VERSION 5.7 ;
  NOWIREEXTENSIONATPIN ON ;
  DIVIDERCHAR "/" ;
  BUSBITCHARS "[]" ;
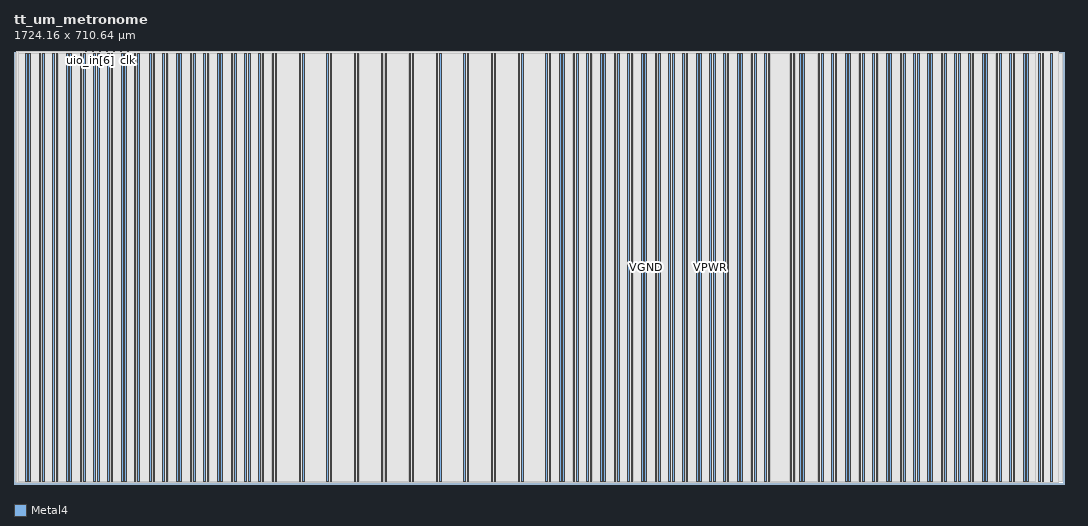
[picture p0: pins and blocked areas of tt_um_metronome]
MACRO tt_um_metronome
  CLASS BLOCK ;
  FOREIGN tt_um_metronome ;
  ORIGIN 0.000 0.000 ;
  SIZE 1724.160 BY 710.640 ;
  PIN VGND
    DIRECTION INOUT ;
    USE GROUND ;
    PORT
      LAYER Metal4 ;
        RECT 24.480 3.780 27.290 706.860 ;
    END
    PORT
      LAYER Metal4 ;
        RECT 46.960 3.780 49.770 706.860 ;
    END
    PORT
      LAYER Metal4 ;
        RECT 69.440 3.780 72.250 706.860 ;
    END
    PORT
      LAYER Metal4 ;
        RECT 91.920 3.780 94.730 706.860 ;
    END
    PORT
      LAYER Metal4 ;
        RECT 114.400 3.780 117.210 706.860 ;
    END
    PORT
      LAYER Metal4 ;
        RECT 136.880 3.780 139.690 706.860 ;
    END
    PORT
      LAYER Metal4 ;
        RECT 159.360 3.780 162.170 706.860 ;
    END
    PORT
      LAYER Metal4 ;
        RECT 181.840 3.780 184.650 706.860 ;
    END
    PORT
      LAYER Metal4 ;
        RECT 202.550 3.780 205.360 706.860 ;
    END
    PORT
      LAYER Metal4 ;
        RECT 228.300 3.780 231.110 706.860 ;
    END
    PORT
      LAYER Metal4 ;
        RECT 249.950 3.780 252.760 706.860 ;
    END
    PORT
      LAYER Metal4 ;
        RECT 272.430 3.780 275.240 706.860 ;
    END
    PORT
      LAYER Metal4 ;
        RECT 294.910 3.780 297.720 706.860 ;
    END
    PORT
      LAYER Metal4 ;
        RECT 317.390 3.780 320.200 706.860 ;
    END
    PORT
      LAYER Metal4 ;
        RECT 339.870 3.780 342.680 706.860 ;
    END
    PORT
      LAYER Metal4 ;
        RECT 362.350 3.780 365.160 706.860 ;
    END
    PORT
      LAYER Metal4 ;
        RECT 384.830 3.780 387.640 706.860 ;
    END
    PORT
      LAYER Metal4 ;
        RECT 407.310 3.780 410.120 706.860 ;
    END
    PORT
      LAYER Metal4 ;
        RECT 429.480 3.560 431.580 707.080 ;
    END
    PORT
      LAYER Metal4 ;
        RECT 474.440 3.560 476.540 707.080 ;
    END
    PORT
      LAYER Metal4 ;
        RECT 519.400 3.560 521.500 707.080 ;
    END
    PORT
      LAYER Metal4 ;
        RECT 564.360 3.560 566.460 707.080 ;
    END
    PORT
      LAYER Metal4 ;
        RECT 609.320 3.560 611.420 707.080 ;
    END
    PORT
      LAYER Metal4 ;
        RECT 654.280 3.560 656.380 707.080 ;
    END
    PORT
      LAYER Metal4 ;
        RECT 699.240 3.560 701.340 707.080 ;
    END
    PORT
      LAYER Metal4 ;
        RECT 744.200 3.560 746.300 707.080 ;
    END
    PORT
      LAYER Metal4 ;
        RECT 789.160 3.560 791.260 707.080 ;
    END
    PORT
      LAYER Metal4 ;
        RECT 834.120 3.560 836.220 707.080 ;
    END
    PORT
      LAYER Metal4 ;
        RECT 879.080 3.560 881.180 707.080 ;
    END
    PORT
      LAYER Metal4 ;
        RECT 901.200 3.780 904.010 706.860 ;
    END
    PORT
      LAYER Metal4 ;
        RECT 923.680 3.780 926.490 706.860 ;
    END
    PORT
      LAYER Metal4 ;
        RECT 946.160 3.780 948.970 706.860 ;
    END
    PORT
      LAYER Metal4 ;
        RECT 968.640 3.780 971.450 706.860 ;
    END
    PORT
      LAYER Metal4 ;
        RECT 991.120 3.780 993.930 706.860 ;
    END
    PORT
      LAYER Metal4 ;
        RECT 1013.600 3.780 1016.410 706.860 ;
    END
    PORT
      LAYER Metal4 ;
        RECT 1036.080 3.780 1038.890 706.860 ;
    END
    PORT
      LAYER Metal4 ;
        RECT 1058.560 3.780 1061.370 706.860 ;
    END
    PORT
      LAYER Metal4 ;
        RECT 1081.040 3.780 1083.850 706.860 ;
    END
    PORT
      LAYER Metal4 ;
        RECT 1103.520 3.780 1106.330 706.860 ;
    END
    PORT
      LAYER Metal4 ;
        RECT 1126.000 3.780 1128.810 706.860 ;
    END
    PORT
      LAYER Metal4 ;
        RECT 1148.480 3.780 1151.290 706.860 ;
    END
    PORT
      LAYER Metal4 ;
        RECT 1170.960 3.780 1173.770 706.860 ;
    END
    PORT
      LAYER Metal4 ;
        RECT 1193.440 3.780 1196.250 706.860 ;
    END
    PORT
      LAYER Metal4 ;
        RECT 1215.920 3.780 1218.730 706.860 ;
    END
    PORT
      LAYER Metal4 ;
        RECT 1238.400 3.780 1241.210 706.860 ;
    END
    PORT
      LAYER Metal4 ;
        RECT 1274.430 3.780 1277.240 706.860 ;
    END
    PORT
      LAYER Metal4 ;
        RECT 1289.880 3.780 1292.690 706.860 ;
    END
    PORT
      LAYER Metal4 ;
        RECT 1325.910 3.780 1328.720 706.860 ;
    END
    PORT
      LAYER Metal4 ;
        RECT 1348.390 3.780 1351.200 706.860 ;
    END
    PORT
      LAYER Metal4 ;
        RECT 1370.870 3.780 1373.680 706.860 ;
    END
    PORT
      LAYER Metal4 ;
        RECT 1393.350 3.780 1396.160 706.860 ;
    END
    PORT
      LAYER Metal4 ;
        RECT 1415.830 3.780 1418.640 706.860 ;
    END
    PORT
      LAYER Metal4 ;
        RECT 1438.310 3.780 1441.120 706.860 ;
    END
    PORT
      LAYER Metal4 ;
        RECT 1460.790 3.780 1463.600 706.860 ;
    END
    PORT
      LAYER Metal4 ;
        RECT 1483.270 3.780 1486.080 706.860 ;
    END
    PORT
      LAYER Metal4 ;
        RECT 1505.750 3.780 1508.560 706.860 ;
    END
    PORT
      LAYER Metal4 ;
        RECT 1528.230 3.780 1531.040 706.860 ;
    END
    PORT
      LAYER Metal4 ;
        RECT 1550.710 3.780 1553.520 706.860 ;
    END
    PORT
      LAYER Metal4 ;
        RECT 1573.190 3.780 1576.000 706.860 ;
    END
    PORT
      LAYER Metal4 ;
        RECT 1595.670 3.780 1598.480 706.860 ;
    END
    PORT
      LAYER Metal4 ;
        RECT 1618.150 3.780 1620.960 706.860 ;
    END
    PORT
      LAYER Metal4 ;
        RECT 1640.630 3.780 1643.440 706.860 ;
    END
    PORT
      LAYER Metal4 ;
        RECT 1663.110 3.780 1665.920 706.860 ;
    END
    PORT
      LAYER Metal4 ;
        RECT 1688.360 3.560 1690.460 707.080 ;
    END
  END VGND
  PIN VPWR
    DIRECTION INOUT ;
    USE POWER ;
    PORT
      LAYER Metal4 ;
        RECT 18.860 3.780 21.670 706.860 ;
    END
    PORT
      LAYER Metal4 ;
        RECT 41.340 3.780 44.150 706.860 ;
    END
    PORT
      LAYER Metal4 ;
        RECT 63.820 3.780 66.630 706.860 ;
    END
    PORT
      LAYER Metal4 ;
        RECT 86.300 3.780 89.110 706.860 ;
    END
    PORT
      LAYER Metal4 ;
        RECT 108.780 3.780 111.590 706.860 ;
    END
    PORT
      LAYER Metal4 ;
        RECT 131.260 3.780 134.070 706.860 ;
    END
    PORT
      LAYER Metal4 ;
        RECT 153.740 3.780 156.550 706.860 ;
    END
    PORT
      LAYER Metal4 ;
        RECT 176.220 3.780 179.030 706.860 ;
    END
    PORT
      LAYER Metal4 ;
        RECT 197.400 3.780 200.210 706.860 ;
    END
    PORT
      LAYER Metal4 ;
        RECT 223.150 3.780 225.960 706.860 ;
    END
    PORT
      LAYER Metal4 ;
        RECT 244.330 3.780 247.140 706.860 ;
    END
    PORT
      LAYER Metal4 ;
        RECT 266.810 3.780 269.620 706.860 ;
    END
    PORT
      LAYER Metal4 ;
        RECT 289.290 3.780 292.100 706.860 ;
    END
    PORT
      LAYER Metal4 ;
        RECT 311.770 3.780 314.580 706.860 ;
    END
    PORT
      LAYER Metal4 ;
        RECT 334.250 3.780 337.060 706.860 ;
    END
    PORT
      LAYER Metal4 ;
        RECT 356.730 3.780 359.540 706.860 ;
    END
    PORT
      LAYER Metal4 ;
        RECT 379.210 3.780 382.020 706.860 ;
    END
    PORT
      LAYER Metal4 ;
        RECT 401.690 3.780 404.500 706.860 ;
    END
    PORT
      LAYER Metal4 ;
        RECT 423.860 3.560 425.960 707.080 ;
    END
    PORT
      LAYER Metal4 ;
        RECT 468.820 3.560 470.920 707.080 ;
    END
    PORT
      LAYER Metal4 ;
        RECT 513.780 3.560 515.880 707.080 ;
    END
    PORT
      LAYER Metal4 ;
        RECT 558.740 3.560 560.840 707.080 ;
    END
    PORT
      LAYER Metal4 ;
        RECT 603.700 3.560 605.800 707.080 ;
    END
    PORT
      LAYER Metal4 ;
        RECT 648.660 3.560 650.760 707.080 ;
    END
    PORT
      LAYER Metal4 ;
        RECT 693.620 3.560 695.720 707.080 ;
    END
    PORT
      LAYER Metal4 ;
        RECT 738.580 3.560 740.680 707.080 ;
    END
    PORT
      LAYER Metal4 ;
        RECT 783.540 3.560 785.640 707.080 ;
    END
    PORT
      LAYER Metal4 ;
        RECT 828.500 3.560 830.600 707.080 ;
    END
    PORT
      LAYER Metal4 ;
        RECT 873.460 3.560 875.560 707.080 ;
    END
    PORT
      LAYER Metal4 ;
        RECT 895.580 3.780 898.390 706.860 ;
    END
    PORT
      LAYER Metal4 ;
        RECT 918.060 3.780 920.870 706.860 ;
    END
    PORT
      LAYER Metal4 ;
        RECT 940.540 3.780 943.350 706.860 ;
    END
    PORT
      LAYER Metal4 ;
        RECT 963.020 3.780 965.830 706.860 ;
    END
    PORT
      LAYER Metal4 ;
        RECT 985.500 3.780 988.310 706.860 ;
    END
    PORT
      LAYER Metal4 ;
        RECT 1007.980 3.780 1010.790 706.860 ;
    END
    PORT
      LAYER Metal4 ;
        RECT 1030.460 3.780 1033.270 706.860 ;
    END
    PORT
      LAYER Metal4 ;
        RECT 1052.940 3.780 1055.750 706.860 ;
    END
    PORT
      LAYER Metal4 ;
        RECT 1075.420 3.780 1078.230 706.860 ;
    END
    PORT
      LAYER Metal4 ;
        RECT 1097.900 3.780 1100.710 706.860 ;
    END
    PORT
      LAYER Metal4 ;
        RECT 1120.380 3.780 1123.190 706.860 ;
    END
    PORT
      LAYER Metal4 ;
        RECT 1142.860 3.780 1145.670 706.860 ;
    END
    PORT
      LAYER Metal4 ;
        RECT 1165.340 3.780 1168.150 706.860 ;
    END
    PORT
      LAYER Metal4 ;
        RECT 1187.820 3.780 1190.630 706.860 ;
    END
    PORT
      LAYER Metal4 ;
        RECT 1210.300 3.780 1213.110 706.860 ;
    END
    PORT
      LAYER Metal4 ;
        RECT 1232.780 3.780 1235.590 706.860 ;
    END
    PORT
      LAYER Metal4 ;
        RECT 1279.580 3.780 1282.390 706.860 ;
    END
    PORT
      LAYER Metal4 ;
        RECT 1295.030 3.780 1297.840 706.860 ;
    END
    PORT
      LAYER Metal4 ;
        RECT 1320.290 3.780 1323.100 706.860 ;
    END
    PORT
      LAYER Metal4 ;
        RECT 1342.770 3.780 1345.580 706.860 ;
    END
    PORT
      LAYER Metal4 ;
        RECT 1365.250 3.780 1368.060 706.860 ;
    END
    PORT
      LAYER Metal4 ;
        RECT 1387.730 3.780 1390.540 706.860 ;
    END
    PORT
      LAYER Metal4 ;
        RECT 1410.210 3.780 1413.020 706.860 ;
    END
    PORT
      LAYER Metal4 ;
        RECT 1432.690 3.780 1435.500 706.860 ;
    END
    PORT
      LAYER Metal4 ;
        RECT 1455.170 3.780 1457.980 706.860 ;
    END
    PORT
      LAYER Metal4 ;
        RECT 1477.650 3.780 1480.460 706.860 ;
    END
    PORT
      LAYER Metal4 ;
        RECT 1500.130 3.780 1502.940 706.860 ;
    END
    PORT
      LAYER Metal4 ;
        RECT 1522.610 3.780 1525.420 706.860 ;
    END
    PORT
      LAYER Metal4 ;
        RECT 1545.090 3.780 1547.900 706.860 ;
    END
    PORT
      LAYER Metal4 ;
        RECT 1567.570 3.780 1570.380 706.860 ;
    END
    PORT
      LAYER Metal4 ;
        RECT 1590.050 3.780 1592.860 706.860 ;
    END
    PORT
      LAYER Metal4 ;
        RECT 1612.530 3.780 1615.340 706.860 ;
    END
    PORT
      LAYER Metal4 ;
        RECT 1635.010 3.780 1637.820 706.860 ;
    END
    PORT
      LAYER Metal4 ;
        RECT 1657.490 3.780 1660.300 706.860 ;
    END
    PORT
      LAYER Metal4 ;
        RECT 1682.740 3.560 1684.840 707.080 ;
    END
    PORT
      LAYER Metal4 ;
        RECT 1702.470 3.780 1704.570 706.860 ;
    END
  END VPWR
  PIN clk
    DIRECTION INPUT ;
    USE SIGNAL ;
    ANTENNAGATEAREA 2.901600 ;
    PORT
      LAYER Metal4 ;
        RECT 187.050 709.640 187.350 710.640 ;
    END
  END clk
  PIN ena
    DIRECTION INPUT ;
    USE SIGNAL ;
    PORT
      LAYER Metal4 ;
        RECT 190.890 709.640 191.190 710.640 ;
    END
  END ena
  PIN rst_n
    DIRECTION INPUT ;
    USE SIGNAL ;
    ANTENNAGATEAREA 0.180700 ;
    PORT
      LAYER Metal4 ;
        RECT 183.210 709.640 183.510 710.640 ;
    END
  END rst_n
  PIN ui_in[0]
    DIRECTION INPUT ;
    USE SIGNAL ;
    ANTENNAGATEAREA 0.180700 ;
    PORT
      LAYER Metal4 ;
        RECT 179.370 709.640 179.670 710.640 ;
    END
  END ui_in[0]
  PIN ui_in[1]
    DIRECTION INPUT ;
    USE SIGNAL ;
    ANTENNAGATEAREA 0.180700 ;
    PORT
      LAYER Metal4 ;
        RECT 175.530 709.640 175.830 710.640 ;
    END
  END ui_in[1]
  PIN ui_in[2]
    DIRECTION INPUT ;
    USE SIGNAL ;
    ANTENNAGATEAREA 0.180700 ;
    PORT
      LAYER Metal4 ;
        RECT 171.690 709.640 171.990 710.640 ;
    END
  END ui_in[2]
  PIN ui_in[3]
    DIRECTION INPUT ;
    USE SIGNAL ;
    ANTENNAGATEAREA 0.180700 ;
    PORT
      LAYER Metal4 ;
        RECT 167.850 709.640 168.150 710.640 ;
    END
  END ui_in[3]
  PIN ui_in[4]
    DIRECTION INPUT ;
    USE SIGNAL ;
    ANTENNAGATEAREA 0.180700 ;
    PORT
      LAYER Metal4 ;
        RECT 164.010 709.640 164.310 710.640 ;
    END
  END ui_in[4]
  PIN ui_in[5]
    DIRECTION INPUT ;
    USE SIGNAL ;
    ANTENNAGATEAREA 0.180700 ;
    PORT
      LAYER Metal4 ;
        RECT 160.170 709.640 160.470 710.640 ;
    END
  END ui_in[5]
  PIN ui_in[6]
    DIRECTION INPUT ;
    USE SIGNAL ;
    ANTENNAGATEAREA 0.180700 ;
    PORT
      LAYER Metal4 ;
        RECT 156.330 709.640 156.630 710.640 ;
    END
  END ui_in[6]
  PIN ui_in[7]
    DIRECTION INPUT ;
    USE SIGNAL ;
    ANTENNAGATEAREA 0.180700 ;
    PORT
      LAYER Metal4 ;
        RECT 152.490 709.640 152.790 710.640 ;
    END
  END ui_in[7]
  PIN uio_in[0]
    DIRECTION INPUT ;
    USE SIGNAL ;
    ANTENNAGATEAREA 0.180700 ;
    PORT
      LAYER Metal4 ;
        RECT 148.650 709.640 148.950 710.640 ;
    END
  END uio_in[0]
  PIN uio_in[1]
    DIRECTION INPUT ;
    USE SIGNAL ;
    ANTENNAGATEAREA 0.180700 ;
    PORT
      LAYER Metal4 ;
        RECT 144.810 709.640 145.110 710.640 ;
    END
  END uio_in[1]
  PIN uio_in[2]
    DIRECTION INPUT ;
    USE SIGNAL ;
    ANTENNAGATEAREA 0.180700 ;
    PORT
      LAYER Metal4 ;
        RECT 140.970 709.640 141.270 710.640 ;
    END
  END uio_in[2]
  PIN uio_in[3]
    DIRECTION INPUT ;
    USE SIGNAL ;
    ANTENNAGATEAREA 0.180700 ;
    PORT
      LAYER Metal4 ;
        RECT 137.130 709.640 137.430 710.640 ;
    END
  END uio_in[3]
  PIN uio_in[4]
    DIRECTION INPUT ;
    USE SIGNAL ;
    ANTENNAGATEAREA 0.180700 ;
    PORT
      LAYER Metal4 ;
        RECT 133.290 709.640 133.590 710.640 ;
    END
  END uio_in[4]
  PIN uio_in[5]
    DIRECTION INPUT ;
    USE SIGNAL ;
    ANTENNAGATEAREA 0.180700 ;
    PORT
      LAYER Metal4 ;
        RECT 129.450 709.640 129.750 710.640 ;
    END
  END uio_in[5]
  PIN uio_in[6]
    DIRECTION INPUT ;
    USE SIGNAL ;
    ANTENNAGATEAREA 0.180700 ;
    PORT
      LAYER Metal4 ;
        RECT 125.610 709.640 125.910 710.640 ;
    END
  END uio_in[6]
  PIN uio_in[7]
    DIRECTION INPUT ;
    USE SIGNAL ;
    ANTENNAGATEAREA 0.180700 ;
    PORT
      LAYER Metal4 ;
        RECT 121.770 709.640 122.070 710.640 ;
    END
  END uio_in[7]
  PIN uio_oe[0]
    DIRECTION OUTPUT ;
    USE SIGNAL ;
    ANTENNADIFFAREA 0.708600 ;
    PORT
      LAYER Metal4 ;
        RECT 56.490 709.640 56.790 710.640 ;
    END
  END uio_oe[0]
  PIN uio_oe[1]
    DIRECTION OUTPUT ;
    USE SIGNAL ;
    ANTENNADIFFAREA 0.708600 ;
    PORT
      LAYER Metal4 ;
        RECT 52.650 709.640 52.950 710.640 ;
    END
  END uio_oe[1]
  PIN uio_oe[2]
    DIRECTION OUTPUT ;
    USE SIGNAL ;
    ANTENNADIFFAREA 0.708600 ;
    PORT
      LAYER Metal4 ;
        RECT 48.810 709.640 49.110 710.640 ;
    END
  END uio_oe[2]
  PIN uio_oe[3]
    DIRECTION OUTPUT ;
    USE SIGNAL ;
    ANTENNADIFFAREA 0.708600 ;
    PORT
      LAYER Metal4 ;
        RECT 44.970 709.640 45.270 710.640 ;
    END
  END uio_oe[3]
  PIN uio_oe[4]
    DIRECTION OUTPUT ;
    USE SIGNAL ;
    ANTENNADIFFAREA 0.708600 ;
    PORT
      LAYER Metal4 ;
        RECT 41.130 709.640 41.430 710.640 ;
    END
  END uio_oe[4]
  PIN uio_oe[5]
    DIRECTION OUTPUT ;
    USE SIGNAL ;
    ANTENNADIFFAREA 0.708600 ;
    PORT
      LAYER Metal4 ;
        RECT 37.290 709.640 37.590 710.640 ;
    END
  END uio_oe[5]
  PIN uio_oe[6]
    DIRECTION OUTPUT ;
    USE SIGNAL ;
    ANTENNADIFFAREA 0.708600 ;
    PORT
      LAYER Metal4 ;
        RECT 33.450 709.640 33.750 710.640 ;
    END
  END uio_oe[6]
  PIN uio_oe[7]
    DIRECTION OUTPUT ;
    USE SIGNAL ;
    ANTENNADIFFAREA 0.708600 ;
    PORT
      LAYER Metal4 ;
        RECT 29.610 709.640 29.910 710.640 ;
    END
  END uio_oe[7]
  PIN uio_out[0]
    DIRECTION OUTPUT ;
    USE SIGNAL ;
    ANTENNADIFFAREA 0.708600 ;
    PORT
      LAYER Metal4 ;
        RECT 87.210 709.640 87.510 710.640 ;
    END
  END uio_out[0]
  PIN uio_out[1]
    DIRECTION OUTPUT ;
    USE SIGNAL ;
    ANTENNADIFFAREA 0.708600 ;
    PORT
      LAYER Metal4 ;
        RECT 83.370 709.640 83.670 710.640 ;
    END
  END uio_out[1]
  PIN uio_out[2]
    DIRECTION OUTPUT ;
    USE SIGNAL ;
    ANTENNADIFFAREA 0.708600 ;
    PORT
      LAYER Metal4 ;
        RECT 79.530 709.640 79.830 710.640 ;
    END
  END uio_out[2]
  PIN uio_out[3]
    DIRECTION OUTPUT ;
    USE SIGNAL ;
    ANTENNADIFFAREA 0.708600 ;
    PORT
      LAYER Metal4 ;
        RECT 75.690 709.640 75.990 710.640 ;
    END
  END uio_out[3]
  PIN uio_out[4]
    DIRECTION OUTPUT ;
    USE SIGNAL ;
    ANTENNADIFFAREA 0.708600 ;
    PORT
      LAYER Metal4 ;
        RECT 71.850 709.640 72.150 710.640 ;
    END
  END uio_out[4]
  PIN uio_out[5]
    DIRECTION OUTPUT ;
    USE SIGNAL ;
    ANTENNADIFFAREA 0.708600 ;
    PORT
      LAYER Metal4 ;
        RECT 68.010 709.640 68.310 710.640 ;
    END
  END uio_out[5]
  PIN uio_out[6]
    DIRECTION OUTPUT ;
    USE SIGNAL ;
    ANTENNADIFFAREA 0.708600 ;
    PORT
      LAYER Metal4 ;
        RECT 64.170 709.640 64.470 710.640 ;
    END
  END uio_out[6]
  PIN uio_out[7]
    DIRECTION OUTPUT ;
    USE SIGNAL ;
    ANTENNADIFFAREA 0.708600 ;
    PORT
      LAYER Metal4 ;
        RECT 60.330 709.640 60.630 710.640 ;
    END
  END uio_out[7]
  PIN uo_out[0]
    DIRECTION OUTPUT ;
    USE SIGNAL ;
    ANTENNADIFFAREA 0.708600 ;
    PORT
      LAYER Metal4 ;
        RECT 117.930 709.640 118.230 710.640 ;
    END
  END uo_out[0]
  PIN uo_out[1]
    DIRECTION OUTPUT ;
    USE SIGNAL ;
    ANTENNADIFFAREA 0.708600 ;
    PORT
      LAYER Metal4 ;
        RECT 114.090 709.640 114.390 710.640 ;
    END
  END uo_out[1]
  PIN uo_out[2]
    DIRECTION OUTPUT ;
    USE SIGNAL ;
    ANTENNADIFFAREA 0.708600 ;
    PORT
      LAYER Metal4 ;
        RECT 110.250 709.640 110.550 710.640 ;
    END
  END uo_out[2]
  PIN uo_out[3]
    DIRECTION OUTPUT ;
    USE SIGNAL ;
    ANTENNADIFFAREA 0.708600 ;
    PORT
      LAYER Metal4 ;
        RECT 106.410 709.640 106.710 710.640 ;
    END
  END uo_out[3]
  PIN uo_out[4]
    DIRECTION OUTPUT ;
    USE SIGNAL ;
    ANTENNADIFFAREA 0.708600 ;
    PORT
      LAYER Metal4 ;
        RECT 102.570 709.640 102.870 710.640 ;
    END
  END uo_out[4]
  PIN uo_out[5]
    DIRECTION OUTPUT ;
    USE SIGNAL ;
    ANTENNADIFFAREA 0.708600 ;
    PORT
      LAYER Metal4 ;
        RECT 98.730 709.640 99.030 710.640 ;
    END
  END uo_out[5]
  PIN uo_out[6]
    DIRECTION OUTPUT ;
    USE SIGNAL ;
    ANTENNADIFFAREA 0.708600 ;
    PORT
      LAYER Metal4 ;
        RECT 94.890 709.640 95.190 710.640 ;
    END
  END uo_out[6]
  PIN uo_out[7]
    DIRECTION OUTPUT ;
    USE SIGNAL ;
    ANTENNADIFFAREA 0.708600 ;
    PORT
      LAYER Metal4 ;
        RECT 91.050 709.640 91.350 710.640 ;
    END
  END uo_out[7]
  OBS
      LAYER GatPoly ;
        RECT 2.880 3.630 1721.280 707.010 ;
      LAYER Metal1 ;
        RECT 2.880 3.560 1721.280 707.080 ;
      LAYER Metal2 ;
        RECT 3.465 3.215 1715.145 709.945 ;
      LAYER Metal3 ;
        RECT 3.360 3.260 1715.185 709.900 ;
      LAYER Metal4 ;
        RECT 7.620 709.430 29.400 709.640 ;
        RECT 30.120 709.430 33.240 709.640 ;
        RECT 33.960 709.430 37.080 709.640 ;
        RECT 37.800 709.430 40.920 709.640 ;
        RECT 41.640 709.430 44.760 709.640 ;
        RECT 45.480 709.430 48.600 709.640 ;
        RECT 49.320 709.430 52.440 709.640 ;
        RECT 53.160 709.430 56.280 709.640 ;
        RECT 57.000 709.430 60.120 709.640 ;
        RECT 60.840 709.430 63.960 709.640 ;
        RECT 64.680 709.430 67.800 709.640 ;
        RECT 68.520 709.430 71.640 709.640 ;
        RECT 72.360 709.430 75.480 709.640 ;
        RECT 76.200 709.430 79.320 709.640 ;
        RECT 80.040 709.430 83.160 709.640 ;
        RECT 83.880 709.430 87.000 709.640 ;
        RECT 87.720 709.430 90.840 709.640 ;
        RECT 91.560 709.430 94.680 709.640 ;
        RECT 95.400 709.430 98.520 709.640 ;
        RECT 99.240 709.430 102.360 709.640 ;
        RECT 103.080 709.430 106.200 709.640 ;
        RECT 106.920 709.430 110.040 709.640 ;
        RECT 110.760 709.430 113.880 709.640 ;
        RECT 114.600 709.430 117.720 709.640 ;
        RECT 118.440 709.430 121.560 709.640 ;
        RECT 122.280 709.430 125.400 709.640 ;
        RECT 126.120 709.430 129.240 709.640 ;
        RECT 129.960 709.430 133.080 709.640 ;
        RECT 133.800 709.430 136.920 709.640 ;
        RECT 137.640 709.430 140.760 709.640 ;
        RECT 141.480 709.430 144.600 709.640 ;
        RECT 145.320 709.430 148.440 709.640 ;
        RECT 149.160 709.430 152.280 709.640 ;
        RECT 153.000 709.430 156.120 709.640 ;
        RECT 156.840 709.430 159.960 709.640 ;
        RECT 160.680 709.430 163.800 709.640 ;
        RECT 164.520 709.430 167.640 709.640 ;
        RECT 168.360 709.430 171.480 709.640 ;
        RECT 172.200 709.430 175.320 709.640 ;
        RECT 176.040 709.430 179.160 709.640 ;
        RECT 179.880 709.430 183.000 709.640 ;
        RECT 183.720 709.430 186.840 709.640 ;
        RECT 187.560 709.430 190.680 709.640 ;
        RECT 191.400 709.430 1677.220 709.640 ;
        RECT 7.620 707.290 1677.220 709.430 ;
        RECT 7.620 707.070 423.650 707.290 ;
        RECT 7.620 3.780 18.650 707.070 ;
        RECT 21.880 3.780 24.270 707.070 ;
        RECT 27.500 3.780 41.130 707.070 ;
        RECT 44.360 3.780 46.750 707.070 ;
        RECT 49.980 3.780 63.610 707.070 ;
        RECT 66.840 3.780 69.230 707.070 ;
        RECT 72.460 3.780 86.090 707.070 ;
        RECT 89.320 3.780 91.710 707.070 ;
        RECT 94.940 3.780 108.570 707.070 ;
        RECT 111.800 3.780 114.190 707.070 ;
        RECT 117.420 3.780 131.050 707.070 ;
        RECT 134.280 3.780 136.670 707.070 ;
        RECT 139.900 3.780 153.530 707.070 ;
        RECT 156.760 3.780 159.150 707.070 ;
        RECT 162.380 3.780 176.010 707.070 ;
        RECT 179.240 3.780 181.630 707.070 ;
        RECT 184.860 3.780 197.190 707.070 ;
        RECT 200.420 3.780 202.340 707.070 ;
        RECT 205.570 3.780 222.940 707.070 ;
        RECT 226.170 3.780 228.090 707.070 ;
        RECT 231.320 3.780 244.120 707.070 ;
        RECT 247.350 3.780 249.740 707.070 ;
        RECT 252.970 3.780 266.600 707.070 ;
        RECT 269.830 3.780 272.220 707.070 ;
        RECT 275.450 3.780 289.080 707.070 ;
        RECT 292.310 3.780 294.700 707.070 ;
        RECT 297.930 3.780 311.560 707.070 ;
        RECT 314.790 3.780 317.180 707.070 ;
        RECT 320.410 3.780 334.040 707.070 ;
        RECT 337.270 3.780 339.660 707.070 ;
        RECT 342.890 3.780 356.520 707.070 ;
        RECT 359.750 3.780 362.140 707.070 ;
        RECT 365.370 3.780 379.000 707.070 ;
        RECT 382.230 3.780 384.620 707.070 ;
        RECT 387.850 3.780 401.480 707.070 ;
        RECT 404.710 3.780 407.100 707.070 ;
        RECT 410.330 3.780 423.650 707.070 ;
        RECT 426.170 3.780 429.270 707.290 ;
        RECT 431.790 3.780 468.610 707.290 ;
        RECT 471.130 3.780 474.230 707.290 ;
        RECT 476.750 3.780 513.570 707.290 ;
        RECT 516.090 3.780 519.190 707.290 ;
        RECT 521.710 3.780 558.530 707.290 ;
        RECT 561.050 3.780 564.150 707.290 ;
        RECT 566.670 3.780 603.490 707.290 ;
        RECT 606.010 3.780 609.110 707.290 ;
        RECT 611.630 3.780 648.450 707.290 ;
        RECT 650.970 3.780 654.070 707.290 ;
        RECT 656.590 3.780 693.410 707.290 ;
        RECT 695.930 3.780 699.030 707.290 ;
        RECT 701.550 3.780 738.370 707.290 ;
        RECT 740.890 3.780 743.990 707.290 ;
        RECT 746.510 3.780 783.330 707.290 ;
        RECT 785.850 3.780 788.950 707.290 ;
        RECT 791.470 3.780 828.290 707.290 ;
        RECT 830.810 3.780 833.910 707.290 ;
        RECT 836.430 3.780 873.250 707.290 ;
        RECT 875.770 3.780 878.870 707.290 ;
        RECT 881.390 707.070 1677.220 707.290 ;
        RECT 881.390 3.780 895.370 707.070 ;
        RECT 898.600 3.780 900.990 707.070 ;
        RECT 904.220 3.780 917.850 707.070 ;
        RECT 921.080 3.780 923.470 707.070 ;
        RECT 926.700 3.780 940.330 707.070 ;
        RECT 943.560 3.780 945.950 707.070 ;
        RECT 949.180 3.780 962.810 707.070 ;
        RECT 966.040 3.780 968.430 707.070 ;
        RECT 971.660 3.780 985.290 707.070 ;
        RECT 988.520 3.780 990.910 707.070 ;
        RECT 994.140 3.780 1007.770 707.070 ;
        RECT 1011.000 3.780 1013.390 707.070 ;
        RECT 1016.620 3.780 1030.250 707.070 ;
        RECT 1033.480 3.780 1035.870 707.070 ;
        RECT 1039.100 3.780 1052.730 707.070 ;
        RECT 1055.960 3.780 1058.350 707.070 ;
        RECT 1061.580 3.780 1075.210 707.070 ;
        RECT 1078.440 3.780 1080.830 707.070 ;
        RECT 1084.060 3.780 1097.690 707.070 ;
        RECT 1100.920 3.780 1103.310 707.070 ;
        RECT 1106.540 3.780 1120.170 707.070 ;
        RECT 1123.400 3.780 1125.790 707.070 ;
        RECT 1129.020 3.780 1142.650 707.070 ;
        RECT 1145.880 3.780 1148.270 707.070 ;
        RECT 1151.500 3.780 1165.130 707.070 ;
        RECT 1168.360 3.780 1170.750 707.070 ;
        RECT 1173.980 3.780 1187.610 707.070 ;
        RECT 1190.840 3.780 1193.230 707.070 ;
        RECT 1196.460 3.780 1210.090 707.070 ;
        RECT 1213.320 3.780 1215.710 707.070 ;
        RECT 1218.940 3.780 1232.570 707.070 ;
        RECT 1235.800 3.780 1238.190 707.070 ;
        RECT 1241.420 3.780 1274.220 707.070 ;
        RECT 1277.450 3.780 1279.370 707.070 ;
        RECT 1282.600 3.780 1289.670 707.070 ;
        RECT 1292.900 3.780 1294.820 707.070 ;
        RECT 1298.050 3.780 1320.080 707.070 ;
        RECT 1323.310 3.780 1325.700 707.070 ;
        RECT 1328.930 3.780 1342.560 707.070 ;
        RECT 1345.790 3.780 1348.180 707.070 ;
        RECT 1351.410 3.780 1365.040 707.070 ;
        RECT 1368.270 3.780 1370.660 707.070 ;
        RECT 1373.890 3.780 1387.520 707.070 ;
        RECT 1390.750 3.780 1393.140 707.070 ;
        RECT 1396.370 3.780 1410.000 707.070 ;
        RECT 1413.230 3.780 1415.620 707.070 ;
        RECT 1418.850 3.780 1432.480 707.070 ;
        RECT 1435.710 3.780 1438.100 707.070 ;
        RECT 1441.330 3.780 1454.960 707.070 ;
        RECT 1458.190 3.780 1460.580 707.070 ;
        RECT 1463.810 3.780 1477.440 707.070 ;
        RECT 1480.670 3.780 1483.060 707.070 ;
        RECT 1486.290 3.780 1499.920 707.070 ;
        RECT 1503.150 3.780 1505.540 707.070 ;
        RECT 1508.770 3.780 1522.400 707.070 ;
        RECT 1525.630 3.780 1528.020 707.070 ;
        RECT 1531.250 3.780 1544.880 707.070 ;
        RECT 1548.110 3.780 1550.500 707.070 ;
        RECT 1553.730 3.780 1567.360 707.070 ;
        RECT 1570.590 3.780 1572.980 707.070 ;
        RECT 1576.210 3.780 1589.840 707.070 ;
        RECT 1593.070 3.780 1595.460 707.070 ;
        RECT 1598.690 3.780 1612.320 707.070 ;
        RECT 1615.550 3.780 1617.940 707.070 ;
        RECT 1621.170 3.780 1634.800 707.070 ;
        RECT 1638.030 3.780 1640.420 707.070 ;
        RECT 1643.650 3.780 1657.280 707.070 ;
        RECT 1660.510 3.780 1662.900 707.070 ;
        RECT 1666.130 3.780 1677.220 707.070 ;
  END
END tt_um_metronome
END LIBRARY

